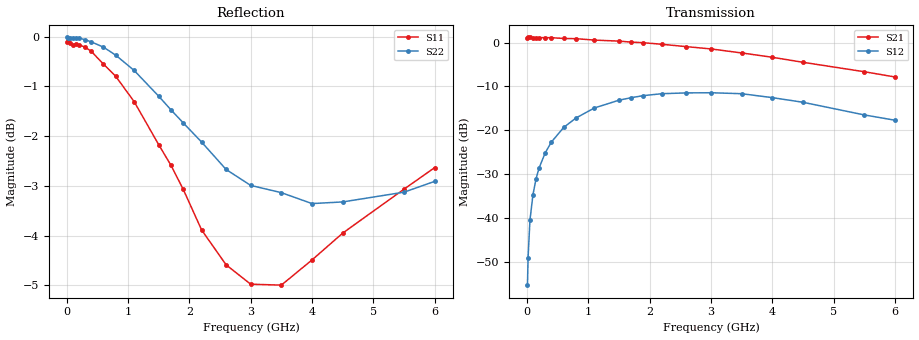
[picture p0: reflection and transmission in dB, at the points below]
! SIEMENS Small Signal Semiconductors
! BFP181
! Si NPN RF Bipolar Junction Transistor in SOT143
! VCE = 0.75 V  IC = 0.3 mA
! Common Emitter S-Parameters:  March  1996
# GHz  S  MA  R  50
!  f  S11  S21  S12  S22
! GHz  MAG  ANG  MAG  ANG  MAG  ANG  MAG  ANG
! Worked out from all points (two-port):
!   36 points, 10 MHz to 6 GHz, reference 50 ohm
!   highest |S21| = 1.19 dB at 20 MHz (marker M1); lowest = -7.9 dB at 6 GHz (marker M2)
!   |S21| within 3 dB of the highest: start of sweep to 3.199 GHz
!   lowest |S11| = -5.0 dB at 3.5 GHz (marker M3), VSWR 3.57, Z = 14.4 + j8.06 ohm
!   |S11| at or under -10 dB: nowhere
!   |S22| runs from -3.4 to 0.0 dB; largest |S21 - S12| = 1.1
!   S11 on the Smith chart (normalised r, x): 10 MHz: open; 800 MHz: 0.35, -2.54; 1.7 GHz: 0.28, -0.93; 2.6 GHz: 0.28, -0.28; 4 GHz: 0.29, +0.36; 6 GHz: 0.31, +1.01
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0.01  0.9878 -0.7  1.124 179.9  0.0017 83.9  0.9984 -0.2
0.02  0.9901 -1.0  1.147 179.6  0.0035 87.7  0.998 -0.5
0.05  0.9865 -2.3  1.147 177.2  0.0093 90.9  0.9978 -1.4
0.1  0.9808 -5.3  1.126 174.5  0.0184 86.0  0.9971 -2.8
0.15  0.9839 -8.1  1.141 171.6  0.0279 84.0  0.997 -4.2
0.2  0.9815 -10.7  1.139 168.7  0.0371 82.2  0.9969 -5.6
0.3  0.9761 -15.9  1.139 163.7  0.0552 78.1  0.993 -8.4
0.4  0.9669 -20.9  1.138 157.1  0.0732 74.3  0.9882 -11.2
0.6  0.9385 -31.7  1.115 146.4  0.1074 66.0  0.9762 -16.6
0.8  0.9124 -42.4  1.109 135.7  0.1376 58.3  0.9581 -21.9
1.1  0.8605 -58.2  1.068 120.1  0.1792 47.0  0.9249 -29.4
1.5  0.7789 -80.4  1.04 100.7  0.2197 33.2  0.8714 -38.7
1.7  0.7426 -91.8  1.013 91.6  0.2351 26.7  0.8443 -42.9
1.9  0.7024 -103.5  0.997 82.2  0.248 20.7  0.8192 -46.7
2.2  0.6393 -121.4  0.957 68.6  0.2609 12.2  0.7835 -52.3
2.6  0.5896 -146.8  0.899 53.1  0.2664 1.8  0.7353 -59.1
3  0.5638 -171.5  0.847 37.4  0.2676 -8.8  0.7087 -66.0
3.5  0.5626 160.1  0.762 20.2  0.2609 -19.5  0.6969 -74.4
4  0.5964 137.7  0.68 5.3  0.2353 -29.2  0.6795 -84.6
4.5  0.6346 119.9  0.596 -7.5  0.2083 -37.6  0.6821 -95.6
5.5  0.7026 95.8  0.465 -26.4  0.1493 -42.5  0.6977 -118.5
6  0.7386 86.9  0.405 -33.7  0.1299 -39.7  0.7154 -130.1
